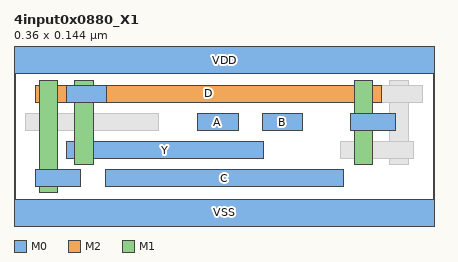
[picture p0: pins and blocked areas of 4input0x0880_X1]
MACRO 4input0x0880_X1
  CLASS CORE ;
  ORIGIN 0 0 ;
  FOREIGN 4input0x0880_X1 0 0 ;
  SIZE 0.3600 BY 0.1440 ;
  SYMMETRY X Y ;
  SITE coresite ;
  PIN A
    DIRECTION INPUT ;
    USE SIGNAL ;
    PORT
      LAYER M0 ;
        RECT 0.1570 0.0770 0.1920 0.0910 ;
    END
  END A
  PIN B
    DIRECTION INPUT ;
    USE SIGNAL ;
    PORT
      LAYER M0 ;
        RECT 0.2130 0.0770 0.2470 0.0910 ;
    END
  END B
  PIN C
    DIRECTION INPUT ;
    USE SIGNAL ;
    PORT
      LAYER M0 ;
        RECT 0.0780 0.0290 0.2820 0.0430 ;
    END
  END C
  PIN D
    DIRECTION INPUT ;
    USE SIGNAL ;
    PORT
      LAYER M2 ;
        RECT 0.0180 0.1010 0.3150 0.1150 ;
      LAYER M1 ;
        RECT 0.0220 0.0240 0.0370 0.1200 ;
        RECT 0.2920 0.0480 0.3070 0.1200 ;
      LAYER M0 ;
        RECT 0.2880 0.0770 0.3270 0.0910 ;
        RECT 0.0180 0.0290 0.0570 0.0430 ;
    END
  END D
  PIN Y
    DIRECTION OUTPUT ;
    USE SIGNAL ;
    PORT
      LAYER M1 ;
        RECT 0.0520 0.0480 0.0680 0.1200 ;
      LAYER M0 ;
        RECT 0.0450 0.1010 0.0790 0.1150 ;
        RECT 0.0450 0.0530 0.2140 0.0670 ;
    END
  END Y
  PIN VDD
    DIRECTION INOUT ;
    USE POWER ;
    SHAPE ABUTMENT ;
    PORT
      LAYER M0 ;
        RECT 0.0000 0.1260 0.3600 0.1620 ;
    END
  END VDD
  PIN VSS
    DIRECTION INOUT ;
    USE GROUND ;
    SHAPE ABUTMENT ;
    PORT
      LAYER M0 ;
        RECT 0.0000 -0.0180 0.3600 0.0180 ;
    END
  END VSS
  OBS
    LAYER V1 ;
      RECT 0.0230 0.1010 0.0370 0.1150 ;
      RECT 0.2930 0.1010 0.3070 0.1150 ;
    LAYER M1 ;
      RECT 0.3220 0.0480 0.3380 0.1200 ;
    LAYER V0 ;
      RECT 0.0530 0.1010 0.0670 0.1150 ;
      RECT 0.0530 0.0530 0.0670 0.0670 ;
      RECT 0.3230 0.1010 0.3370 0.1150 ;
      RECT 0.3230 0.0530 0.3370 0.0670 ;
      RECT 0.0230 0.0290 0.0370 0.0430 ;
      RECT 0.2930 0.0770 0.3070 0.0910 ;
    LAYER M0 ;
      RECT 0.2800 0.0530 0.3420 0.0670 ;
      RECT 0.0100 0.0770 0.1240 0.0910 ;
      RECT 0.1230 0.1010 0.3500 0.1150 ;
  END
END 4input0x0880_X1
